VERSION 5.8 ;
BUSBITCHARS "[]" ;
DIVIDERCHAR "/" ;
UNITS
    DATABASE MICRONS 1000 ;
END UNITS

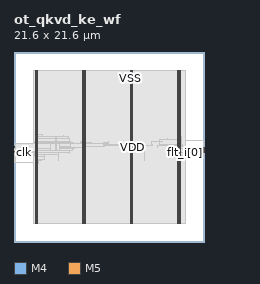
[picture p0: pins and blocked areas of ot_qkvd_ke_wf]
MACRO ot_qkvd_ke_wf
  FOREIGN ot_qkvd_ke_wf 0 0 ;
  CLASS BLOCK ;
  SIZE 21.6 BY 21.6 ;
  PIN clk
    DIRECTION INPUT ;
    USE SIGNAL ;
    PORT
      LAYER M4 ;
        RECT  0 10.128 0.084 10.152 ;
    END
  END clk
  PIN fault
    DIRECTION OUTPUT ;
    USE SIGNAL ;
    PORT
      LAYER M4 ;
        RECT  0 10.224 0.084 10.248 ;
    END
  END fault
  PIN fault_cause[0]
    DIRECTION OUTPUT ;
    USE SIGNAL ;
    PORT
      LAYER M4 ;
        RECT  0 10.32 0.084 10.344 ;
    END
  END fault_cause[0]
  PIN fault_cause[1]
    DIRECTION OUTPUT ;
    USE SIGNAL ;
    PORT
      LAYER M4 ;
        RECT  0 10.416 0.084 10.44 ;
    END
  END fault_cause[1]
  PIN fault_cause[2]
    DIRECTION OUTPUT ;
    USE SIGNAL ;
    PORT
      LAYER M4 ;
        RECT  0 10.512 0.084 10.536 ;
    END
  END fault_cause[2]
  PIN fault_cause[3]
    DIRECTION OUTPUT ;
    USE SIGNAL ;
    PORT
      LAYER M4 ;
        RECT  0 10.608 0.084 10.632 ;
    END
  END fault_cause[3]
  PIN fault_cause[4]
    DIRECTION OUTPUT ;
    USE SIGNAL ;
    PORT
      LAYER M4 ;
        RECT  0 10.704 0.084 10.728 ;
    END
  END fault_cause[4]
  PIN flt_i[0]
    DIRECTION INPUT ;
    USE SIGNAL ;
    PORT
      LAYER M4 ;
        RECT  21.516 10.128 21.6 10.152 ;
    END
  END flt_i[0]
  PIN flt_i[1]
    DIRECTION INPUT ;
    USE SIGNAL ;
    PORT
      LAYER M4 ;
        RECT  21.516 10.224 21.6 10.248 ;
    END
  END flt_i[1]
  PIN flt_i[2]
    DIRECTION INPUT ;
    USE SIGNAL ;
    PORT
      LAYER M4 ;
        RECT  21.516 10.32 21.6 10.344 ;
    END
  END flt_i[2]
  PIN flt_i[3]
    DIRECTION INPUT ;
    USE SIGNAL ;
    PORT
      LAYER M4 ;
        RECT  21.516 10.416 21.6 10.44 ;
    END
  END flt_i[3]
  PIN flt_i[4]
    DIRECTION INPUT ;
    USE SIGNAL ;
    PORT
      LAYER M4 ;
        RECT  21.516 10.512 21.6 10.536 ;
    END
  END flt_i[4]
  PIN flt_i[5]
    DIRECTION INPUT ;
    USE SIGNAL ;
    PORT
      LAYER M4 ;
        RECT  21.516 10.608 21.6 10.632 ;
    END
  END flt_i[5]
  PIN rst_n
    DIRECTION INPUT ;
    USE SIGNAL ;
    PORT
      LAYER M4 ;
        RECT  0 10.8 0.084 10.824 ;
    END
  END rst_n
  PIN rsw
    DIRECTION OUTPUT ;
    USE SIGNAL ;
    PORT
      LAYER M4 ;
        RECT  21.516 10.704 21.6 10.728 ;
    END
  END rsw
  PIN VDD
    DIRECTION INOUT ;
    USE POWER ;
    PORT
      LAYER M5 ;
        RECT  18.792 2.151 18.912 19.449 ;
        RECT  13.392 2.151 13.512 19.449 ;
        RECT  7.992 2.151 8.112 19.449 ;
        RECT  2.592 2.151 2.712 19.449 ;
    END
  END VDD
  PIN VSS
    DIRECTION INOUT ;
    USE GROUND ;
    PORT
      LAYER M5 ;
        RECT  18.6 2.137 18.72 19.463 ;
        RECT  13.2 2.137 13.32 19.463 ;
        RECT  7.8 2.137 7.92 19.463 ;
        RECT  2.4 2.137 2.52 19.463 ;
    END
  END VSS
  # OT_OBS_CLOSED layer=M5 d_um=1.536 added=0
  OBS
    LAYER RVTN ;
     RECT  2.16 2.16 19.44 2.295 ;
     RECT  2.16 2.565 19.44 2.835 ;
     RECT  2.16 3.105 19.44 3.375 ;
     RECT  2.16 3.645 19.44 3.915 ;
     RECT  2.16 4.185 19.44 4.455 ;
     RECT  2.16 4.725 19.44 4.995 ;
     RECT  2.16 5.265 19.44 5.535 ;
     RECT  2.16 5.805 19.44 6.075 ;
     RECT  2.16 6.345 19.44 6.615 ;
     RECT  2.16 6.885 19.44 7.155 ;
     RECT  2.16 7.425 19.44 7.695 ;
     RECT  2.16 7.965 19.44 8.235 ;
     RECT  2.16 8.505 19.44 8.775 ;
     RECT  2.16 9.045 19.44 9.315 ;
     RECT  2.16 9.585 19.44 9.855 ;
     RECT  2.16 10.125 19.44 10.395 ;
     RECT  2.16 10.665 19.44 10.935 ;
     RECT  2.16 11.205 19.44 11.475 ;
     RECT  2.16 11.745 19.44 12.015 ;
     RECT  2.16 12.285 19.44 12.555 ;
     RECT  2.16 12.825 19.44 13.095 ;
     RECT  2.16 13.365 19.44 13.635 ;
     RECT  2.16 13.905 19.44 14.175 ;
     RECT  2.16 14.445 19.44 14.715 ;
     RECT  2.16 14.985 19.44 15.255 ;
     RECT  2.16 15.525 19.44 15.795 ;
     RECT  2.16 16.065 19.44 16.335 ;
     RECT  2.16 16.605 19.44 16.875 ;
     RECT  2.16 17.145 19.44 17.415 ;
     RECT  2.16 17.685 19.44 17.955 ;
     RECT  2.16 18.225 19.44 18.495 ;
     RECT  2.16 18.765 19.44 19.035 ;
     RECT  2.16 19.305 19.44 19.44 ;
    LAYER RVTP ;
     RECT  2.16 2.295 19.44 2.565 ;
     RECT  2.16 2.835 19.44 3.105 ;
     RECT  2.16 3.375 19.44 3.645 ;
     RECT  2.16 3.915 19.44 4.185 ;
     RECT  2.16 4.455 19.44 4.725 ;
     RECT  2.16 4.995 19.44 5.265 ;
     RECT  2.16 5.535 19.44 5.805 ;
     RECT  2.16 6.075 19.44 6.345 ;
     RECT  2.16 6.615 19.44 6.885 ;
     RECT  2.16 7.155 19.44 7.425 ;
     RECT  2.16 7.695 19.44 7.965 ;
     RECT  2.16 8.235 19.44 8.505 ;
     RECT  2.16 8.775 19.44 9.045 ;
     RECT  2.16 9.315 19.44 9.585 ;
     RECT  2.16 9.855 19.44 10.125 ;
     RECT  2.16 10.395 19.44 10.665 ;
     RECT  2.16 10.935 19.44 11.205 ;
     RECT  2.16 11.475 19.44 11.745 ;
     RECT  2.16 12.015 19.44 12.285 ;
     RECT  2.16 12.555 19.44 12.825 ;
     RECT  2.16 13.095 19.44 13.365 ;
     RECT  2.16 13.635 19.44 13.905 ;
     RECT  2.16 14.175 19.44 14.445 ;
     RECT  2.16 14.715 19.44 14.985 ;
     RECT  2.16 15.255 19.44 15.525 ;
     RECT  2.16 15.795 19.44 16.065 ;
     RECT  2.16 16.335 19.44 16.605 ;
     RECT  2.16 16.875 19.44 17.145 ;
     RECT  2.16 17.415 19.44 17.685 ;
     RECT  2.16 17.955 19.44 18.225 ;
     RECT  2.16 18.495 19.44 18.765 ;
     RECT  2.16 19.035 19.44 19.305 ;
    LAYER M1 ;
     RECT  2.16 2.151 19.44 19.449 ;
    LAYER M2 ;
     RECT  0.103 9.054 2.16 9.072 ;
     RECT  0.139 10.206 2.16 10.224 ;
     RECT  2.16 2.151 19.44 19.449 ;
     RECT  19.44 9.828 19.463 10.584 ;
     RECT  19.463 10.134 19.967 10.584 ;
     RECT  19.967 10.17 20.507 10.584 ;
     RECT  20.507 10.17 21.515 10.188 ;
     RECT  19.44 11.484 21.515 11.502 ;
    LAYER M3 ;
     RECT  2.415 2.143 2.505 2.413 ;
     RECT  7.815 2.143 7.905 2.413 ;
     RECT  13.215 2.143 13.305 2.413 ;
     RECT  18.615 2.143 18.705 2.413 ;
     RECT  2.415 2.413 2.697 8.941 ;
     RECT  2.415 8.941 2.754 9.085 ;
     RECT  2.415 9.085 2.826 9.211 ;
     RECT  2.415 9.211 3.114 9.391 ;
     RECT  18.615 2.413 18.897 9.625 ;
     RECT  2.415 9.391 3.438 9.751 ;
     RECT  18.036 9.625 18.897 9.823 ;
     RECT  2.304 9.751 3.438 9.931 ;
     RECT  5.004 9.247 5.022 9.931 ;
     RECT  18.036 9.823 19.458 10.123 ;
     RECT  18.036 10.123 19.926 10.129 ;
     RECT  2.304 9.931 5.022 10.165 ;
     RECT  6.264 10.093 6.282 10.165 ;
     RECT  0.108 9.049 0.126 10.201 ;
     RECT  18.036 10.129 19.962 10.201 ;
     RECT  0.108 10.201 0.162 10.253 ;
     RECT  2.304 10.165 6.282 10.435 ;
     RECT  0.144 10.253 0.162 10.445 ;
     RECT  17.892 10.201 19.962 10.463 ;
     RECT  2.304 10.435 6.678 10.633 ;
     RECT  17.892 10.463 19.458 10.637 ;
     RECT  20.484 10.561 20.502 10.733 ;
     RECT  2.304 10.633 6.822 10.741 ;
     RECT  7.815 2.413 8.097 10.741 ;
     RECT  14.832 9.247 14.85 10.769 ;
     RECT  2.304 10.741 8.097 10.795 ;
     RECT  17.892 10.637 19.242 10.859 ;
     RECT  2.268 10.795 8.097 10.867 ;
     RECT  10.296 10.843 10.314 10.939 ;
     RECT  16.344 10.705 16.362 10.939 ;
     RECT  13.215 2.413 13.497 10.987 ;
     RECT  16.344 10.939 16.506 11.003 ;
     RECT  2.268 10.867 8.406 11.011 ;
     RECT  15.588 10.975 15.606 11.011 ;
     RECT  16.488 11.003 16.506 11.011 ;
     RECT  17.892 10.859 19.134 11.011 ;
     RECT  11.988 10.939 12.006 11.035 ;
     RECT  12.816 10.987 13.497 11.035 ;
     RECT  11.988 11.035 13.497 11.039 ;
     RECT  15.588 11.011 15.75 11.129 ;
     RECT  16.488 11.011 19.134 11.129 ;
     RECT  2.268 11.011 8.73 11.165 ;
     RECT  12.492 11.039 13.497 11.165 ;
     RECT  7.596 11.165 8.73 11.173 ;
     RECT  10.188 10.939 10.314 11.179 ;
     RECT  2.268 11.165 6.822 11.201 ;
     RECT  10.152 11.179 10.314 11.209 ;
     RECT  7.596 11.173 8.802 11.273 ;
     RECT  10.152 11.209 10.782 11.273 ;
     RECT  2.268 11.201 6.786 11.309 ;
     RECT  2.268 11.309 6.426 11.399 ;
     RECT  7.596 11.273 8.097 11.399 ;
     RECT  10.764 11.273 10.782 11.399 ;
     RECT  2.268 11.399 6.282 11.435 ;
     RECT  15.588 11.129 15.606 11.453 ;
     RECT  21.492 10.165 21.51 11.507 ;
     RECT  16.488 11.129 19.098 11.669 ;
     RECT  16.488 11.669 17.658 11.705 ;
     RECT  17.424 11.705 17.442 11.741 ;
     RECT  2.415 11.435 6.282 11.777 ;
     RECT  2.415 11.777 6.21 11.939 ;
     RECT  18.615 11.669 19.098 11.939 ;
     RECT  2.415 11.939 4.734 11.975 ;
     RECT  2.415 11.975 3.51 12.011 ;
     RECT  4.716 11.975 4.734 12.029 ;
     RECT  5.616 11.939 5.706 12.047 ;
     RECT  5.616 12.047 5.634 12.083 ;
     RECT  2.415 12.011 3.294 12.245 ;
     RECT  2.415 12.245 2.697 19.187 ;
     RECT  7.815 11.399 8.097 19.187 ;
     RECT  13.215 11.165 13.497 19.187 ;
     RECT  18.615 11.939 18.897 19.187 ;
     RECT  2.415 19.187 2.505 19.457 ;
     RECT  7.815 19.187 7.905 19.457 ;
     RECT  13.215 19.187 13.305 19.457 ;
     RECT  18.615 19.187 18.705 19.457 ;
    LAYER M4 ;
     RECT  0.06 10.128 0.133 10.824 ;
     RECT  0.133 10.128 0.179 11.208 ;
     RECT  0.179 10.32 2.408 11.208 ;
     RECT  2.408 2.148 2.512 19.452 ;
     RECT  2.512 2.418 2.704 19.182 ;
     RECT  2.704 10.608 4.165 11.208 ;
     RECT  4.165 10.416 4.7 11.208 ;
     RECT  4.7 10.416 4.787 12.024 ;
     RECT  4.787 10.416 5.177 11.208 ;
     RECT  5.177 10.848 6.433 11.208 ;
     RECT  6.433 10.752 7.808 11.208 ;
     RECT  7.808 2.148 7.912 19.452 ;
     RECT  7.912 2.418 8.104 19.182 ;
     RECT  8.104 10.848 10.181 11.208 ;
     RECT  10.181 10.848 10.325 11.064 ;
     RECT  10.325 10.944 12.017 11.064 ;
     RECT  12.017 10.992 13.208 11.064 ;
     RECT  13.208 2.148 13.312 19.452 ;
     RECT  13.312 2.418 13.504 19.182 ;
     RECT  13.504 10.992 15.577 11.016 ;
     RECT  15.577 10.992 15.617 11.448 ;
     RECT  15.617 11.424 16.913 11.448 ;
     RECT  18.608 2.148 18.712 19.452 ;
     RECT  18.712 2.418 18.904 19.182 ;
     RECT  18.904 10.224 19.897 10.632 ;
     RECT  19.897 10.128 20.473 10.632 ;
     RECT  20.473 10.128 21.564 10.728 ;
    LAYER M5 ;
     RECT  2.4 2.137 2.52 2.151 ;
     RECT  7.8 2.137 7.92 2.151 ;
     RECT  13.2 2.137 13.32 2.151 ;
     RECT  18.6 2.137 18.72 2.151 ;
     RECT  0.144 10.117 0.168 11.219 ;
     RECT  4.752 10.933 4.776 12.035 ;
     RECT  2.4 2.151 2.712 19.449 ;
     RECT  7.8 2.151 8.112 19.449 ;
     RECT  13.2 2.151 13.512 19.449 ;
     RECT  18.6 2.151 18.912 19.449 ;
     RECT  2.4 19.449 2.52 19.463 ;
     RECT  7.8 19.449 7.92 19.463 ;
     RECT  13.2 19.449 13.32 19.463 ;
     RECT  18.6 19.449 18.72 19.463 ;
  END
END ot_qkvd_ke_wf
END LIBRARY
